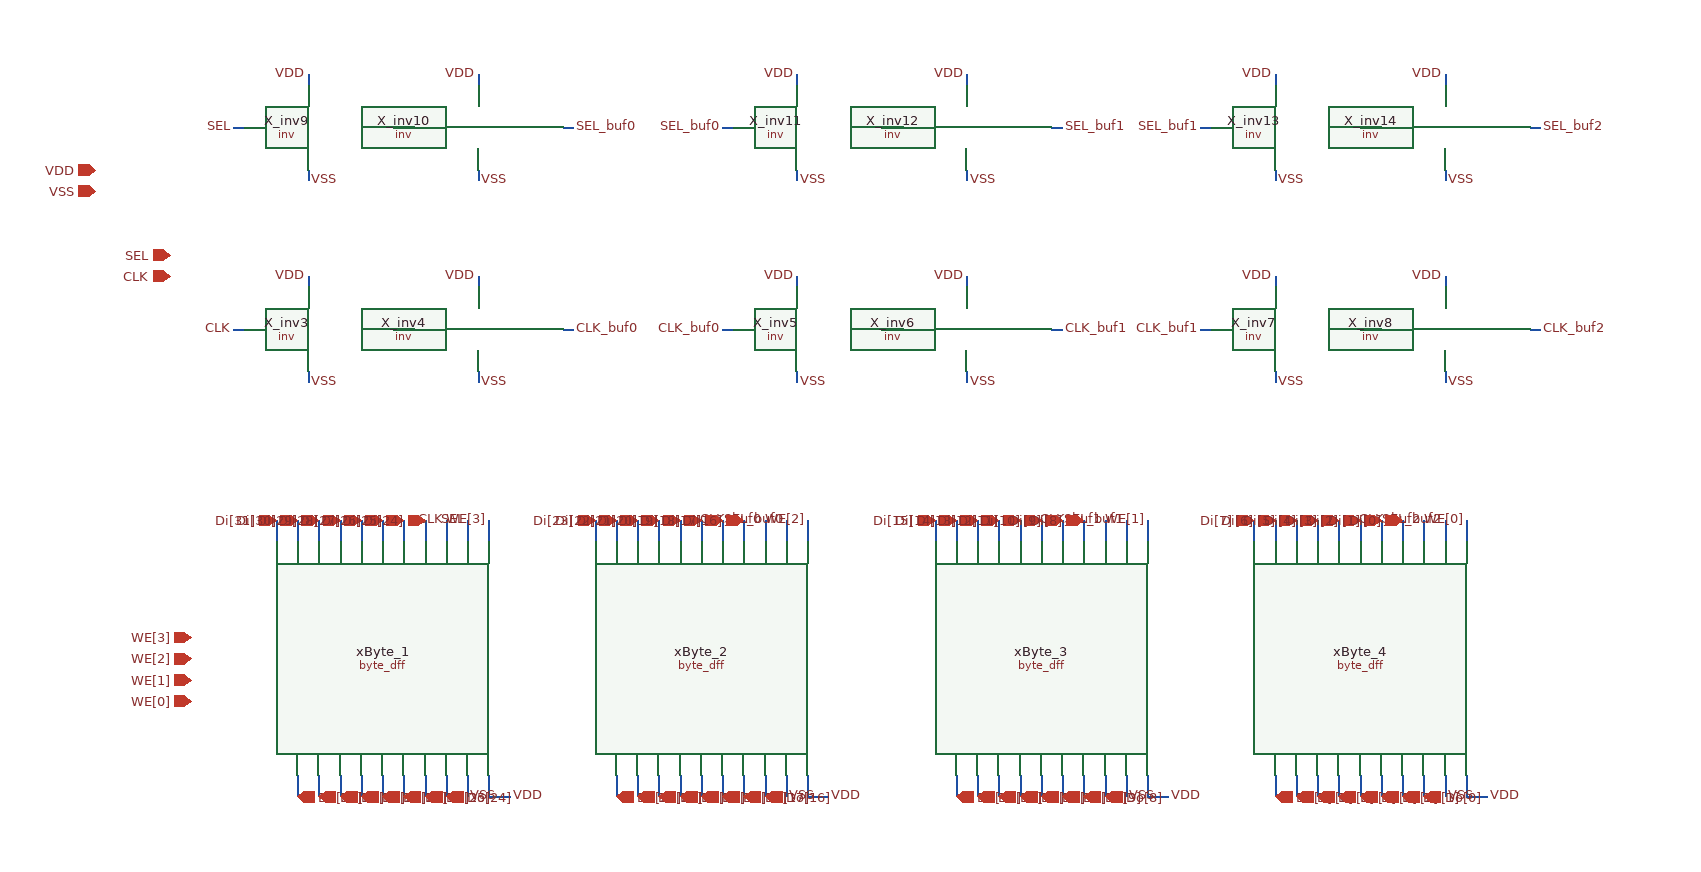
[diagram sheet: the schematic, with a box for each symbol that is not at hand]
v {xschem version=3.0.0 file_version=1.2 }
G {}
K {}
V {}
S {}
E {}
N 230 -390 230 -370 {
lab=Di[31]}
N 250 -390 250 -370 {
lab=Di[30]}
N 270 -390 270 -370 {
lab=Di[29]}
N 290 -390 290 -370 {
lab=Di[28]}
N 310 -390 310 -370 {
lab=Di[27]}
N 330 -390 330 -370 {
lab=Di[26]}
N 350 -390 350 -370 {
lab=Di[25]}
N 370 -390 370 -370 {
lab=Di[24]}
N 390 -390 390 -370 {
lab=CLK}
N 410 -390 410 -370 {
lab=SEL}
N 430 -390 430 -370 {
lab=WE[3]}
N 250 -150 250 -130 {
lab=Do[31]}
N 270 -150 270 -130 {
lab=Do[30]}
N 290 -150 290 -130 {
lab=Do[29]}
N 310 -150 310 -130 {
lab=Do[28]}
N 330 -150 330 -130 {
lab=Do[27]}
N 350 -150 350 -130 {
lab=Do[26]}
N 370 -150 370 -130 {
lab=Do[25]}
N 390 -150 390 -130 {
lab=Do[24]}
N 410 -150 410 -130 {
lab=VSS}
N 430 -150 430 -130 {
lab=VDD}
N 430 -130 450 -130 {
lab=VDD}
N 530 -390 530 -370 {
lab=Di[23]}
N 550 -390 550 -370 {
lab=Di[22]}
N 570 -390 570 -370 {
lab=Di[21]}
N 590 -390 590 -370 {
lab=Di[20]}
N 610 -390 610 -370 {
lab=Di[19]}
N 630 -390 630 -370 {
lab=Di[18]}
N 650 -390 650 -370 {
lab=Di[17]}
N 670 -390 670 -370 {
lab=Di[16]}
N 690 -390 690 -370 {
lab=CLK_buf0}
N 710 -390 710 -370 {
lab=SEL_buf0}
N 730 -390 730 -370 {
lab=WE[2]}
N 550 -150 550 -130 {
lab=Do[23]}
N 570 -150 570 -130 {
lab=Do[22]}
N 590 -150 590 -130 {
lab=Do[21]}
N 610 -150 610 -130 {
lab=Do[20]}
N 630 -150 630 -130 {
lab=Do[19]}
N 650 -150 650 -130 {
lab=Do[18]}
N 670 -150 670 -130 {
lab=Do[17]}
N 690 -150 690 -130 {
lab=Do[16]}
N 710 -150 710 -130 {
lab=VSS}
N 730 -150 730 -130 {
lab=VDD}
N 730 -130 750 -130 {
lab=VDD}
N 850 -390 850 -370 {
lab=Di[15]}
N 870 -390 870 -370 {
lab=Di[14]}
N 890 -390 890 -370 {
lab=Di[13]}
N 910 -390 910 -370 {
lab=Di[12]}
N 930 -390 930 -370 {
lab=Di[11]}
N 950 -390 950 -370 {
lab=Di[10]}
N 970 -390 970 -370 {
lab=Di[9]}
N 990 -390 990 -370 {
lab=Di[8]}
N 1010 -390 1010 -370 {
lab=CLK_buf1}
N 1030 -390 1030 -370 {
lab=SEL_buf1}
N 1050 -390 1050 -370 {
lab=WE[1]}
N 870 -150 870 -130 {
lab=Do[15]}
N 890 -150 890 -130 {
lab=Do[14]}
N 910 -150 910 -130 {
lab=Do[13]}
N 930 -150 930 -130 {
lab=Do[12]}
N 950 -150 950 -130 {
lab=Do[11]}
N 970 -150 970 -130 {
lab=Do[10]}
N 990 -150 990 -130 {
lab=Do[9]}
N 1010 -150 1010 -130 {
lab=Do[8]}
N 1030 -150 1030 -130 {
lab=VSS}
N 1050 -150 1050 -130 {
lab=VDD}
N 1050 -130 1070 -130 {
lab=VDD}
N 1150 -390 1150 -370 {
lab=Di[7]}
N 1170 -390 1170 -370 {
lab=Di[6]}
N 1190 -390 1190 -370 {
lab=Di[5]}
N 1210 -390 1210 -370 {
lab=Di[4]}
N 1230 -390 1230 -370 {
lab=Di[3]}
N 1250 -390 1250 -370 {
lab=Di[2]}
N 1270 -390 1270 -370 {
lab=Di[1]}
N 1290 -390 1290 -370 {
lab=Di[0]}
N 1310 -390 1310 -370 {
lab=CLK_buf2}
N 1330 -390 1330 -370 {
lab=SEL_buf}
N 1350 -390 1350 -370 {
lab=WE[0]}
N 1170 -150 1170 -130 {
lab=Do[7]}
N 1190 -150 1190 -130 {
lab=Do[6]}
N 1210 -150 1210 -130 {
lab=Do[5]}
N 1230 -150 1230 -130 {
lab=Do[4]}
N 1250 -150 1250 -130 {
lab=Do[3]}
N 1270 -150 1270 -130 {
lab=Do[2]}
N 1290 -150 1290 -130 {
lab=Do[1]}
N 1310 -150 1310 -130 {
lab=Do[0]}
N 1330 -150 1330 -130 {
lab=VSS}
N 1350 -150 1350 -130 {
lab=VDD}
N 1350 -130 1370 -130 {
lab=VDD}
N 340 -570 360 -570 {
lab=#net1}
N 260 -620 260 -610 {
lab=VDD}
N 420 -620 420 -610 {
lab=VDD}
N 260 -530 260 -520 {
lab=VSS}
N 420 -530 420 -520 {
lab=VSS}
N 190 -570 200 -570 {
lab=CLK}
N 500 -570 510 -570 {
lab=CLK_buf0}
N 800 -570 820 -570 {
lab=#net2}
N 720 -620 720 -610 {
lab=VDD}
N 880 -620 880 -610 {
lab=VDD}
N 720 -530 720 -520 {
lab=VSS}
N 880 -530 880 -520 {
lab=VSS}
N 650 -570 660 -570 {
lab=CLK_buf0}
N 960 -570 970 -570 {
lab=CLK_buf1}
N 1250 -570 1270 -570 {
lab=#net3}
N 1170 -620 1170 -610 {
lab=VDD}
N 1330 -620 1330 -610 {
lab=VDD}
N 1170 -530 1170 -520 {
lab=VSS}
N 1330 -530 1330 -520 {
lab=VSS}
N 1100 -570 1110 -570 {
lab=CLK_buf1}
N 1410 -570 1420 -570 {
lab=CLK_buf2}
N 340 -760 360 -760 {
lab=#net4}
N 260 -810 260 -800 {
lab=VDD}
N 420 -810 420 -800 {
lab=VDD}
N 260 -720 260 -710 {
lab=VSS}
N 420 -720 420 -710 {
lab=VSS}
N 190 -760 200 -760 {
lab=SEL}
N 500 -760 510 -760 {
lab=SEL_buf0}
N 800 -760 820 -760 {
lab=#net5}
N 720 -810 720 -800 {
lab=VDD}
N 880 -810 880 -800 {
lab=VDD}
N 720 -720 720 -710 {
lab=VSS}
N 880 -720 880 -710 {
lab=VSS}
N 650 -760 660 -760 {
lab=SEL_buf0}
N 960 -760 970 -760 {
lab=SEL_buf1}
N 1250 -760 1270 -760 {
lab=#net6}
N 1170 -810 1170 -800 {
lab=VDD}
N 1330 -810 1330 -800 {
lab=VDD}
N 1170 -720 1170 -710 {
lab=VSS}
N 1330 -720 1330 -710 {
lab=VSS}
N 1100 -760 1110 -760 {
lab=SEL_buf1}
N 1410 -760 1420 -760 {
lab=SEL_buf2}
C {xschem_lib/byte_dff.sym} 330 -260 1 0 {name=xByte_1 NF=2}
C {ipin.sym} 130 -640 0 0 {name=p1 lab=SEL}
C {lab_wire.sym} 450 -130 2 0 {name=l6 sig_type=std_logic lab=VDD}
C {lab_wire.sym} 410 -130 2 0 {name=l7 sig_type=std_logic lab=VSS}
C {lab_wire.sym} 410 -390 1 0 {name=l8 sig_type=std_logic lab=SEL}
C {ipin.sym} 150 -220 0 0 {name=p2 lab=WE[0]}
C {lab_wire.sym} 430 -390 1 0 {name=l9 sig_type=std_logic lab=WE[3]}
C {lab_wire.sym} 390 -390 1 0 {name=l11 sig_type=std_logic lab=CLK}
C {ipin.sym} 230 -390 1 0 {name=p3 lab=Di[31]}
C {ipin.sym} 250 -390 1 0 {name=p4 lab=Di[30]}
C {ipin.sym} 270 -390 1 0 {name=p5 lab=Di[29]}
C {ipin.sym} 290 -390 1 0 {name=p6 lab=Di[28]}
C {ipin.sym} 310 -390 1 0 {name=p7 lab=Di[27]}
C {ipin.sym} 330 -390 1 0 {name=p8 lab=Di[26]}
C {ipin.sym} 350 -390 1 0 {name=p9 lab=Di[25]}
C {ipin.sym} 370 -390 1 0 {name=p10 lab=Di[24]}
C {opin.sym} 250 -130 1 0 {name=p11 lab=Do[31]}
C {opin.sym} 270 -130 1 0 {name=p12 lab=Do[30]}
C {opin.sym} 290 -130 1 0 {name=p13 lab=Do[29]}
C {opin.sym} 310 -130 1 0 {name=p14 lab=Do[28]}
C {opin.sym} 330 -130 1 0 {name=p15 lab=Do[27]}
C {opin.sym} 350 -130 1 0 {name=p16 lab=Do[26]}
C {opin.sym} 370 -130 1 0 {name=p17 lab=Do[25]}
C {opin.sym} 390 -130 1 0 {name=p18 lab=Do[24]}
C {iopin.sym} 60 -720 0 0 {name=p19 lab=VDD}
C {iopin.sym} 60 -700 0 0 {name=p20 lab=VSS}
C {xschem_lib/byte_dff.sym} 630 -260 1 0 {name=xByte_2 NF=2}
C {lab_wire.sym} 750 -130 2 0 {name=l12 sig_type=std_logic lab=VDD}
C {lab_wire.sym} 710 -130 2 0 {name=l13 sig_type=std_logic lab=VSS}
C {lab_wire.sym} 710 -390 1 0 {name=l14 sig_type=std_logic lab=SEL_buf0}
C {lab_wire.sym} 730 -390 1 0 {name=l15 sig_type=std_logic lab=WE[2]}
C {lab_wire.sym} 690 -390 1 0 {name=l16 sig_type=std_logic lab=CLK_buf0
}
C {ipin.sym} 530 -390 1 0 {name=p21 lab=Di[23]}
C {ipin.sym} 550 -390 1 0 {name=p22 lab=Di[22]}
C {ipin.sym} 570 -390 1 0 {name=p23 lab=Di[21]}
C {ipin.sym} 590 -390 1 0 {name=p24 lab=Di[20]}
C {ipin.sym} 610 -390 1 0 {name=p25 lab=Di[19]}
C {ipin.sym} 630 -390 1 0 {name=p26 lab=Di[18]}
C {ipin.sym} 650 -390 1 0 {name=p27 lab=Di[17]}
C {ipin.sym} 670 -390 1 0 {name=p28 lab=Di[16]}
C {opin.sym} 550 -130 1 0 {name=p29 lab=Do[23]}
C {opin.sym} 570 -130 1 0 {name=p30 lab=Do[22]}
C {opin.sym} 590 -130 1 0 {name=p31 lab=Do[21]}
C {opin.sym} 610 -130 1 0 {name=p32 lab=Do[20]}
C {opin.sym} 630 -130 1 0 {name=p33 lab=Do[19]}
C {opin.sym} 650 -130 1 0 {name=p34 lab=Do[18]}
C {opin.sym} 670 -130 1 0 {name=p35 lab=Do[17]}
C {opin.sym} 690 -130 1 0 {name=p36 lab=Do[16]}
C {xschem_lib/byte_dff.sym} 950 -260 1 0 {name=xByte_3 NF=2}
C {lab_wire.sym} 1070 -130 2 0 {name=l17 sig_type=std_logic lab=VDD}
C {lab_wire.sym} 1030 -130 2 0 {name=l18 sig_type=std_logic lab=VSS}
C {lab_wire.sym} 1030 -390 1 0 {name=l19 sig_type=std_logic lab=SEL_buf1}
C {lab_wire.sym} 1050 -390 1 0 {name=l20 sig_type=std_logic lab=WE[1]}
C {lab_wire.sym} 1010 -390 1 0 {name=l21 sig_type=std_logic lab=CLK_buf1}
C {ipin.sym} 850 -390 1 0 {name=p37 lab=Di[15]}
C {ipin.sym} 870 -390 1 0 {name=p38 lab=Di[14]}
C {ipin.sym} 890 -390 1 0 {name=p39 lab=Di[13]}
C {ipin.sym} 910 -390 1 0 {name=p40 lab=Di[12]}
C {ipin.sym} 930 -390 1 0 {name=p41 lab=Di[11]}
C {ipin.sym} 950 -390 1 0 {name=p42 lab=Di[10]}
C {ipin.sym} 970 -390 1 0 {name=p43 lab=Di[9]}
C {ipin.sym} 990 -390 1 0 {name=p44 lab=Di[8]}
C {opin.sym} 870 -130 1 0 {name=p45 lab=Do[15]}
C {opin.sym} 890 -130 1 0 {name=p46 lab=Do[14]}
C {opin.sym} 910 -130 1 0 {name=p47 lab=Do[13]}
C {opin.sym} 930 -130 1 0 {name=p48 lab=Do[12]}
C {opin.sym} 950 -130 1 0 {name=p49 lab=Do[11]}
C {opin.sym} 970 -130 1 0 {name=p50 lab=Do[10]}
C {opin.sym} 990 -130 1 0 {name=p51 lab=Do[9]}
C {opin.sym} 1010 -130 1 0 {name=p52 lab=Do[8]}
C {xschem_lib/byte_dff.sym} 1250 -260 1 0 {name=xByte_4 NF=2}
C {lab_wire.sym} 1370 -130 2 0 {name=l22 sig_type=std_logic lab=VDD}
C {lab_wire.sym} 1330 -130 2 0 {name=l23 sig_type=std_logic lab=VSS}
C {lab_wire.sym} 1330 -390 1 0 {name=l24 sig_type=std_logic lab=SEL_buf2}
C {lab_wire.sym} 1350 -390 1 0 {name=l25 sig_type=std_logic lab=WE[0]}
C {lab_wire.sym} 1310 -390 1 0 {name=l26 sig_type=std_logic lab=CLK_buf2}
C {ipin.sym} 1150 -390 1 0 {name=p53 lab=Di[7]}
C {ipin.sym} 1170 -390 1 0 {name=p54 lab=Di[6]}
C {ipin.sym} 1190 -390 1 0 {name=p55 lab=Di[5]}
C {ipin.sym} 1210 -390 1 0 {name=p56 lab=Di[4]}
C {ipin.sym} 1230 -390 1 0 {name=p57 lab=Di[3]}
C {ipin.sym} 1250 -390 1 0 {name=p58 lab=Di[2]}
C {ipin.sym} 1270 -390 1 0 {name=p59 lab=Di[1]}
C {ipin.sym} 1290 -390 1 0 {name=p60 lab=Di[0]}
C {opin.sym} 1170 -130 1 0 {name=p61 lab=Do[7]}
C {opin.sym} 1190 -130 1 0 {name=p62 lab=Do[6]}
C {opin.sym} 1210 -130 1 0 {name=p63 lab=Do[5]}
C {opin.sym} 1230 -130 1 0 {name=p64 lab=Do[4]}
C {opin.sym} 1250 -130 1 0 {name=p65 lab=Do[3]}
C {opin.sym} 1270 -130 1 0 {name=p66 lab=Do[2]}
C {opin.sym} 1290 -130 1 0 {name=p67 lab=Do[1]}
C {opin.sym} 1310 -130 1 0 {name=p68 lab=Do[0]}
C {ipin.sym} 150 -240 0 0 {name=p69 lab=WE[1]}
C {ipin.sym} 150 -260 0 0 {name=p70 lab=WE[2]}
C {ipin.sym} 150 -280 0 0 {name=p71 lab=WE[3]}
C {ipin.sym} 130 -620 0 0 {name=p72 lab=CLK}
C {xschem_lib/inv.sym} 200 -530 0 0 {name=X_inv3 NF=2}
C {xschem_lib/inv.sym} 360 -530 0 0 {name=X_inv4 NF=2}
C {lab_wire.sym} 260 -620 1 0 {name=l27 sig_type=std_logic lab=VDD}
C {lab_wire.sym} 260 -520 2 0 {name=l28 sig_type=std_logic lab=VSS}
C {lab_wire.sym} 420 -620 1 0 {name=l29 sig_type=std_logic lab=VDD}
C {lab_wire.sym} 420 -520 2 0 {name=l30 sig_type=std_logic lab=VSS}
C {lab_wire.sym} 510 -570 2 0 {name=l31 sig_type=std_logic lab=CLK_buf0
}
C {lab_wire.sym} 190 -570 0 0 {name=l32 sig_type=std_logic lab=CLK
}
C {xschem_lib/inv.sym} 660 -530 0 0 {name=X_inv5 NF=2}
C {xschem_lib/inv.sym} 820 -530 0 0 {name=X_inv6 NF=2}
C {lab_wire.sym} 720 -620 1 0 {name=l33 sig_type=std_logic lab=VDD}
C {lab_wire.sym} 720 -520 2 0 {name=l34 sig_type=std_logic lab=VSS}
C {lab_wire.sym} 880 -620 1 0 {name=l35 sig_type=std_logic lab=VDD}
C {lab_wire.sym} 880 -520 2 0 {name=l36 sig_type=std_logic lab=VSS}
C {lab_wire.sym} 970 -570 2 0 {name=l37 sig_type=std_logic lab=CLK_buf1
}
C {lab_wire.sym} 650 -570 0 0 {name=l38 sig_type=std_logic lab=CLK_buf0}
C {xschem_lib/inv.sym} 1110 -530 0 0 {name=X_inv7 NF=2}
C {xschem_lib/inv.sym} 1270 -530 0 0 {name=X_inv8 NF=2}
C {lab_wire.sym} 1170 -620 1 0 {name=l39 sig_type=std_logic lab=VDD}
C {lab_wire.sym} 1170 -520 2 0 {name=l40 sig_type=std_logic lab=VSS}
C {lab_wire.sym} 1330 -620 1 0 {name=l41 sig_type=std_logic lab=VDD}
C {lab_wire.sym} 1330 -520 2 0 {name=l42 sig_type=std_logic lab=VSS}
C {lab_wire.sym} 1420 -570 2 0 {name=l43 sig_type=std_logic lab=CLK_buf2
}
C {lab_wire.sym} 1100 -570 0 0 {name=l44 sig_type=std_logic lab=CLK_buf1
}
C {xschem_lib/inv.sym} 200 -720 0 0 {name=X_inv9 NF=2}
C {xschem_lib/inv.sym} 360 -720 0 0 {name=X_inv10 NF=2}
C {lab_wire.sym} 260 -810 1 0 {name=l45 sig_type=std_logic lab=VDD}
C {lab_wire.sym} 260 -710 2 0 {name=l46 sig_type=std_logic lab=VSS}
C {lab_wire.sym} 420 -810 1 0 {name=l47 sig_type=std_logic lab=VDD}
C {lab_wire.sym} 420 -710 2 0 {name=l48 sig_type=std_logic lab=VSS}
C {lab_wire.sym} 510 -760 2 0 {name=l49 sig_type=std_logic lab=SEL_buf0
}
C {lab_wire.sym} 190 -760 0 0 {name=l50 sig_type=std_logic lab=SEL
}
C {xschem_lib/inv.sym} 660 -720 0 0 {name=X_inv11 NF=2}
C {xschem_lib/inv.sym} 820 -720 0 0 {name=X_inv12 NF=2}
C {lab_wire.sym} 720 -810 1 0 {name=l51 sig_type=std_logic lab=VDD}
C {lab_wire.sym} 720 -710 2 0 {name=l52 sig_type=std_logic lab=VSS}
C {lab_wire.sym} 880 -810 1 0 {name=l53 sig_type=std_logic lab=VDD}
C {lab_wire.sym} 880 -710 2 0 {name=l54 sig_type=std_logic lab=VSS}
C {lab_wire.sym} 970 -760 2 0 {name=l55 sig_type=std_logic lab=SEL_buf1
}
C {lab_wire.sym} 650 -760 0 0 {name=l56 sig_type=std_logic lab=SEL_buf0
}
C {xschem_lib/inv.sym} 1110 -720 0 0 {name=X_inv13 NF=2}
C {xschem_lib/inv.sym} 1270 -720 0 0 {name=X_inv14 NF=2}
C {lab_wire.sym} 1170 -810 1 0 {name=l57 sig_type=std_logic lab=VDD}
C {lab_wire.sym} 1170 -710 2 0 {name=l58 sig_type=std_logic lab=VSS}
C {lab_wire.sym} 1330 -810 1 0 {name=l59 sig_type=std_logic lab=VDD}
C {lab_wire.sym} 1330 -710 2 0 {name=l60 sig_type=std_logic lab=VSS}
C {lab_wire.sym} 1420 -760 2 0 {name=l61 sig_type=std_logic lab=SEL_buf2
}
C {lab_wire.sym} 1100 -760 0 0 {name=l62 sig_type=std_logic lab=SEL_buf1
}
